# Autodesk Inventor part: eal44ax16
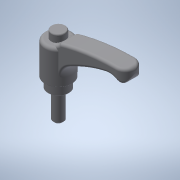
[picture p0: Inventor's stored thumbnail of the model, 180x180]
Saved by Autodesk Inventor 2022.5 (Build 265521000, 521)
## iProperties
Created: 2016-12
Part Number: eal44ax16
Material: 一般
Document SubType Name: Modeling
Designer: imaocorp
Density: 1 g/cm^3
Appearance: 既定
Author: imaocorp
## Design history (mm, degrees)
node "eal44ax16.x_t1"
node "eal44ax16"
node "Base1"
